VERSION 5.7 ;
  NOWIREEXTENSIONATPIN ON ;
  DIVIDERCHAR "/" ;
  BUSBITCHARS "[]" ;
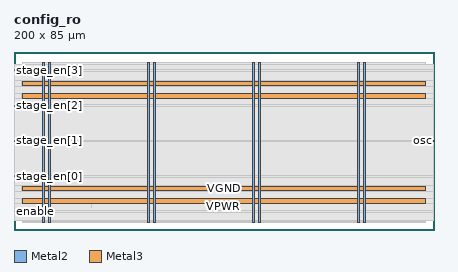
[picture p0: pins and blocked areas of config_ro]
MACRO config_ro
  CLASS BLOCK ;
  FOREIGN config_ro ;
  ORIGIN 0.000 0.000 ;
  SIZE 200.000 BY 85.000 ;
  PIN VGND
    DIRECTION INOUT ;
    USE GROUND ;
    PORT
      LAYER Metal2 ;
        RECT 16.340 3.560 17.340 79.600 ;
    END
    PORT
      LAYER Metal2 ;
        RECT 66.340 3.560 67.340 79.600 ;
    END
    PORT
      LAYER Metal2 ;
        RECT 116.340 3.560 117.340 79.600 ;
    END
    PORT
      LAYER Metal2 ;
        RECT 166.340 3.560 167.340 79.600 ;
    END
    PORT
      LAYER Metal3 ;
        RECT 3.840 18.780 195.840 20.780 ;
    END
    PORT
      LAYER Metal3 ;
        RECT 3.840 68.780 195.840 70.780 ;
    END
  END VGND
  PIN VPWR
    DIRECTION INOUT ;
    USE POWER ;
    PORT
      LAYER Metal2 ;
        RECT 13.340 3.560 14.340 79.600 ;
    END
    PORT
      LAYER Metal2 ;
        RECT 63.340 3.560 64.340 79.600 ;
    END
    PORT
      LAYER Metal2 ;
        RECT 113.340 3.560 114.340 79.600 ;
    END
    PORT
      LAYER Metal2 ;
        RECT 163.340 3.560 164.340 79.600 ;
    END
    PORT
      LAYER Metal3 ;
        RECT 3.840 12.780 195.840 14.780 ;
    END
    PORT
      LAYER Metal3 ;
        RECT 3.840 62.780 195.840 64.780 ;
    END
  END VPWR
  PIN enable
    DIRECTION INPUT ;
    USE SIGNAL ;
    ANTENNAGATEAREA 0.180700 ;
    PORT
      LAYER Metal3 ;
        RECT 0.000 8.620 0.400 9.020 ;
    END
  END enable
  PIN osc
    DIRECTION OUTPUT ;
    USE SIGNAL ;
    ANTENNADIFFAREA 0.708600 ;
    PORT
      LAYER Metal3 ;
        RECT 199.600 42.220 200.000 42.620 ;
    END
  END osc
  PIN stage_en[0]
    DIRECTION INPUT ;
    USE SIGNAL ;
    ANTENNAGATEAREA 0.180700 ;
    PORT
      LAYER Metal3 ;
        RECT 0.000 25.420 0.400 25.820 ;
    END
  END stage_en[0]
  PIN stage_en[1]
    DIRECTION INPUT ;
    USE SIGNAL ;
    ANTENNAGATEAREA 0.180700 ;
    PORT
      LAYER Metal3 ;
        RECT 0.000 42.220 0.400 42.620 ;
    END
  END stage_en[1]
  PIN stage_en[2]
    DIRECTION INPUT ;
    USE SIGNAL ;
    ANTENNAGATEAREA 0.180700 ;
    PORT
      LAYER Metal3 ;
        RECT 0.000 59.020 0.400 59.420 ;
    END
  END stage_en[2]
  PIN stage_en[3]
    DIRECTION INPUT ;
    USE SIGNAL ;
    ANTENNAGATEAREA 0.180700 ;
    PORT
      LAYER Metal3 ;
        RECT 0.000 75.820 0.400 76.220 ;
    END
  END stage_en[3]
  OBS
      LAYER GatPoly ;
        RECT 3.840 3.630 195.840 79.530 ;
      LAYER Metal1 ;
        RECT 3.840 3.560 195.840 79.600 ;
      LAYER Metal2 ;
        RECT 4.215 4.050 13.130 78.685 ;
        RECT 14.550 4.050 16.130 78.685 ;
        RECT 17.550 4.050 63.130 78.685 ;
        RECT 64.550 4.050 66.130 78.685 ;
        RECT 67.550 4.050 113.130 78.685 ;
        RECT 114.550 4.050 116.130 78.685 ;
        RECT 117.550 4.050 163.130 78.685 ;
        RECT 164.550 4.050 166.130 78.685 ;
        RECT 167.550 4.050 195.945 78.685 ;
      LAYER Metal3 ;
        RECT 0.400 76.430 199.600 78.640 ;
        RECT 0.610 75.610 199.600 76.430 ;
        RECT 0.400 70.990 199.600 75.610 ;
        RECT 0.400 68.570 3.630 70.990 ;
        RECT 196.050 68.570 199.600 70.990 ;
        RECT 0.400 64.990 199.600 68.570 ;
        RECT 0.400 62.570 3.630 64.990 ;
        RECT 196.050 62.570 199.600 64.990 ;
        RECT 0.400 59.630 199.600 62.570 ;
        RECT 0.610 58.810 199.600 59.630 ;
        RECT 0.400 42.830 199.600 58.810 ;
        RECT 0.610 42.010 199.390 42.830 ;
        RECT 0.400 26.030 199.600 42.010 ;
        RECT 0.610 25.210 199.600 26.030 ;
        RECT 0.400 20.990 199.600 25.210 ;
        RECT 0.400 18.570 3.630 20.990 ;
        RECT 196.050 18.570 199.600 20.990 ;
        RECT 0.400 14.990 199.600 18.570 ;
        RECT 0.400 12.570 3.630 14.990 ;
        RECT 196.050 12.570 199.600 14.990 ;
        RECT 0.400 9.230 199.600 12.570 ;
        RECT 0.610 8.410 199.600 9.230 ;
        RECT 0.400 4.520 199.600 8.410 ;
      LAYER Metal4 ;
        RECT 36.860 10.775 37.060 12.325 ;
  END
END config_ro
END LIBRARY

